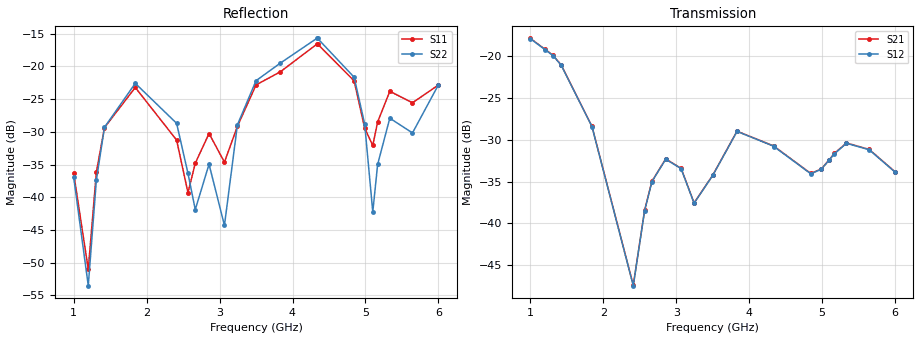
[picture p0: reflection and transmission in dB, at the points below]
!Agilent Technologies,E8364B,MY43040528,A.07.50.67
!Agilent E8364B: A.07.50.67
!Date: Sunday, March 01, 2026 22:04:15
!Correction: S11(Full 2 Port(1,2))
!S21(Full 2 Port(1,2))
!S12(Full 2 Port(1,2))
!S22(Full 2 Port(1,2))
!S2P File: Measurements: S11, S21, S12, S22:
# Hz S  dB  R 50
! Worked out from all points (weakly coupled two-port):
!   451 points, 1 GHz to 6 GHz, reference 50 ohm
!   highest |S21| = -17.86 dB at 1 GHz (marker M1); lowest = -47.4 dB at 2.411 GHz (marker M2)
!   lowest |S11| = -51.0 dB at 1.2 GHz (marker M3), VSWR 1.01, Z = 50.1 - j0.246 ohm
!   |S11| at or under -10 dB: start of sweep to end of sweep
!   |S22| runs from -53.5 to -15.7 dB; largest |S21 - S12| = 0.00055
!   S11 on the Smith chart (normalised r, x): 1 GHz: 1.03, +0.01; 4.333 GHz: 1.23, -0.24; 6 GHz: 0.98, -0.14
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1e9  -36.35 16.9  -17.86 28.6  -17.90 28.7  -36.95 -27.2
1.2e9  -51.03 -60.6  -19.16 -31.6  -19.20 -31.6  -53.53 52.5
1.311111e9  -36.17 -150.0  -19.89 -67.9  -19.93 -67.8  -37.38 124.5
1.422222e9  -29.35 177.8  -21.04 -105.3  -21.06 -105.3  -29.31 98.1
1.844444e9  -23.22 83.3  -28.38 121.5  -28.41 121.6  -22.59 -12.2
2.411111e9  -31.26 5.4  -47.39 -127.5  -47.44 -127.6  -28.70 -126.4
2.566667e9  -39.31 35.9  -38.41 108.3  -38.45 108.4  -36.35 -148.1
2.666667e9  -34.81 71.5  -34.95 63.2  -34.99 63.2  -41.89 -100.9
2.855556e9  -30.26 51.7  -32.27 -13.2  -32.32 -13.2  -34.96 -100.2
3.066667e9  -34.64 47.5  -33.41 -90.7  -33.44 -90.6  -44.31 -75.0
3.244444e9  -29.16 87.1  -37.54 -133.8  -37.57 -133.7  -28.93 -52.3
3.5e9  -22.83 55.0  -34.23 -155.0  -34.26 -155.0  -22.18 -109.6
3.833333e9  -20.82 25.4  -28.96 91.8  -28.99 91.8  -19.49 -160.1
4.333333e9  -16.60 -39.2  -30.72 -87.1  -30.75 -87.1  -15.71 111.5
4.344444e9  -16.59 -40.9  -30.79 -91.1  -30.83 -91.0  -15.73 109.2
4.844444e9  -22.21 -122.8  -34.02 50.1  -34.06 50.1  -21.65 -0.5
4.988889e9  -29.43 -128.8  -33.48 -31.1  -33.51 -31.1  -28.80 -30.8
5.1e9  -32.09 -76.5  -32.35 -91.0  -32.38 -91.0  -42.26 9.7
5.166667e9  -28.49 -61.5  -31.63 -124.7  -31.68 -124.7  -34.99 64.1
5.333333e9  -23.80 -77.6  -30.37 157.5  -30.41 157.5  -27.92 39.2
5.644444e9  -25.56 -103.3  -31.14 30.9  -31.18 30.9  -30.17 19.8
6e9  -22.84 -94.7  -33.82 -70.5  -33.86 -70.6  -22.81 -5.4
